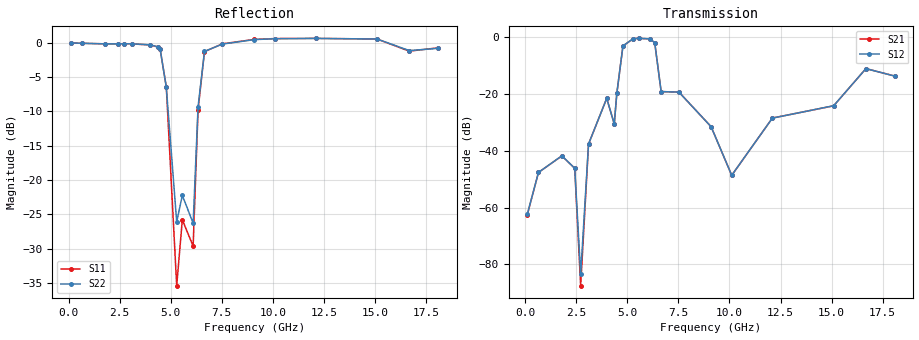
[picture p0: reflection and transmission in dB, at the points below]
! TSB1N18D5G53LV0FWT  S-PARAMETER MODEL  ( General Type )
! Model Generated by TAIYO YUDEN Corporation (https://www.yuden.co.jp/en/)
! Version 1.0
! TAIYO YUDEN Control No. 20160609
! Copyright(c) 2016 TAIYO YUDEN CO.,LTD. All Rights Reserved.
! Products Name : Multilayer Ceramic Devices
! Characteristics :
!  Passband freq : 5150-5925MHz ( At Passband , Insertion Loss : 1.2dB , VSWR 2.0 ),
!  Attenuation : 37 dB min at 100 to 2700MHz, 20dB min at 2700-3600MHz, 22dB min at 10300-12750MHz , Impedance : 50 Ohm ,
!  Case Size : 1.6 x 0.8 / 0.063 x 0.031 [mm/inch] , Thickness : 0.65 / 0.026 [mm/inch]
!  (Conditions: Temperature = 25 degC , DC Bias Current/Voltage = 0A / 0V)
! External Node Assignments :
!  1  o---|-------|---o  2
!  |  BPF  |
! GND o---|-------|---o GND
! Frequency Range : 100MHz  -  18.1GHz  [ 3601 STEP ]
# MHZ S RI R 50
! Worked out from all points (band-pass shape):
!   3601 points, 100 MHz to 18.1 GHz, reference 50 ohm
!   highest |S21| = -0.55 dB at 5.57 GHz (marker M1); lowest = -87.5 dB at 2.715 GHz (marker M2)
!   |S21| within 3 dB of the highest: 4.769 GHz to 6.408 GHz (1.639 GHz wide, 29.3 % of centre)
!   lowest |S11| = -35.4 dB at 5.295 GHz (marker M3), VSWR 1.03, Z = 49.7 - j1.67 ohm
!   |S11| at or under -10 dB: 4.87 GHz to 6.337 GHz (1.467 GHz wide, 26.2 % of centre)
!   |S22| runs from -27.5 to 0.7 dB; largest |S21 - S12| = 0.0026
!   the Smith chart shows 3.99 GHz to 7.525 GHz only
!   S11 on the Smith chart (normalised r, x): 3.99 GHz: 0.05, +1.24; 4.485 GHz: 10, +9; 4.785 GHz: 0.74, -0.90; 6.34 GHz: 1.96, +0.01; 6.655 GHz: 0.15, -0.97; 7.525 GHz: 0.01, -0.16
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100  -0.9959 0.0218  0.000209 0.000709  0.000226 0.000724  -0.9958 0.0213
650  -0.9828 0.1157  0.000917 0.00404  0.00085 0.00406  -0.9829 0.112
1795  -0.9298 0.3105  0.00293 0.00753  0.00294 0.00758  -0.9318 0.3034
2425  -0.8617 0.4675  0.00249 0.00421  0.00249 0.00422  -0.8667 0.4595
2715  -0.8009 0.566  -3.87e-05 1.74e-05  -6.81e-05 -4.43e-07  -0.8088 0.5552
3100  -0.6629 0.7213  -0.00997 -0.00841  -0.00996 -0.00839  -0.678 0.7088
3990  0.2077 0.9396  -0.0813 0.0162  -0.0814 0.0163  0.1437 0.9534
4360  0.8052 0.4651  -0.028 0.00935  -0.028 0.00932  0.753 0.5518
4485  0.8896 0.0875  -0.0288 -0.0971  -0.0289 -0.0972  0.8756 0.1988
4785  0.0957 -0.4687  -0.6916 -0.0127  -0.6918 -0.013  0.1494 -0.4505
5295  -0.00269 -0.0168  0.1416 0.9206  0.1427 0.9216  0.00994 0.0485
5570  0.0157 -0.0489  0.6556 0.6717  0.6566 0.6721  0.0764 0.0125
6100  -0.033 0.00127  0.8322 -0.3924  0.8326 -0.3935  0.0399 -0.0275
6340  0.3242 0.00237  0.1717 -0.7727  0.1722 -0.7737  0.3406 0.00849
6655  -0.0153 -0.8605  -0.0926 -0.0575  -0.0931 -0.0568  0.1237 -0.8545
7525  -0.9322 -0.303  0.0463 -0.0966  0.0459 -0.0964  -0.8871 -0.4068
9100  -1.052 0.0901  0.00176 -0.0263  0.00182 -0.0263  -1.052 0.0392
10110  -1.065 0.1129  0.0036 -0.000775  0.00364 -0.00068  -1.065 0.0827
12100  -1.073 -0.0598  0.0234 0.0292  0.0233 0.0291  -1.071 -0.069
15100  -0.8845 -0.5886  -0.0132 0.0599  -0.0131 0.0602  -0.8908 -0.5806
16680  -0.8606 0.1081  0.0734 0.2665  0.0742 0.2662  -0.8735 0.0645
18100  0.185 0.8989  0.2028 -0.0241  0.2021 -0.0252  0.1392 0.8982
